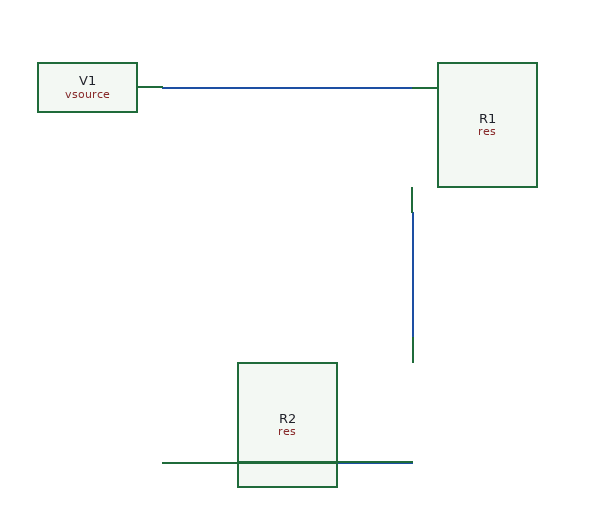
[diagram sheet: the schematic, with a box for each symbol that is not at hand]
v {xschem version=3.4.5 file_version=1.2}
G {}
K {}
V {}
S {}
E {}
C {devices/vsource.sym} 0 0 0 0 {name=V1 value=3.3}
C {devices/res.sym} 200 0 0 0 {name=R1 value=10k}
C {devices/res.sym} 200 200 0 0 {name=R2 value=10k}
N 0 0 200 0 {lab=VDD}
N 200 100 200 200 {}
N 200 300 0 300 {lab=GND}
